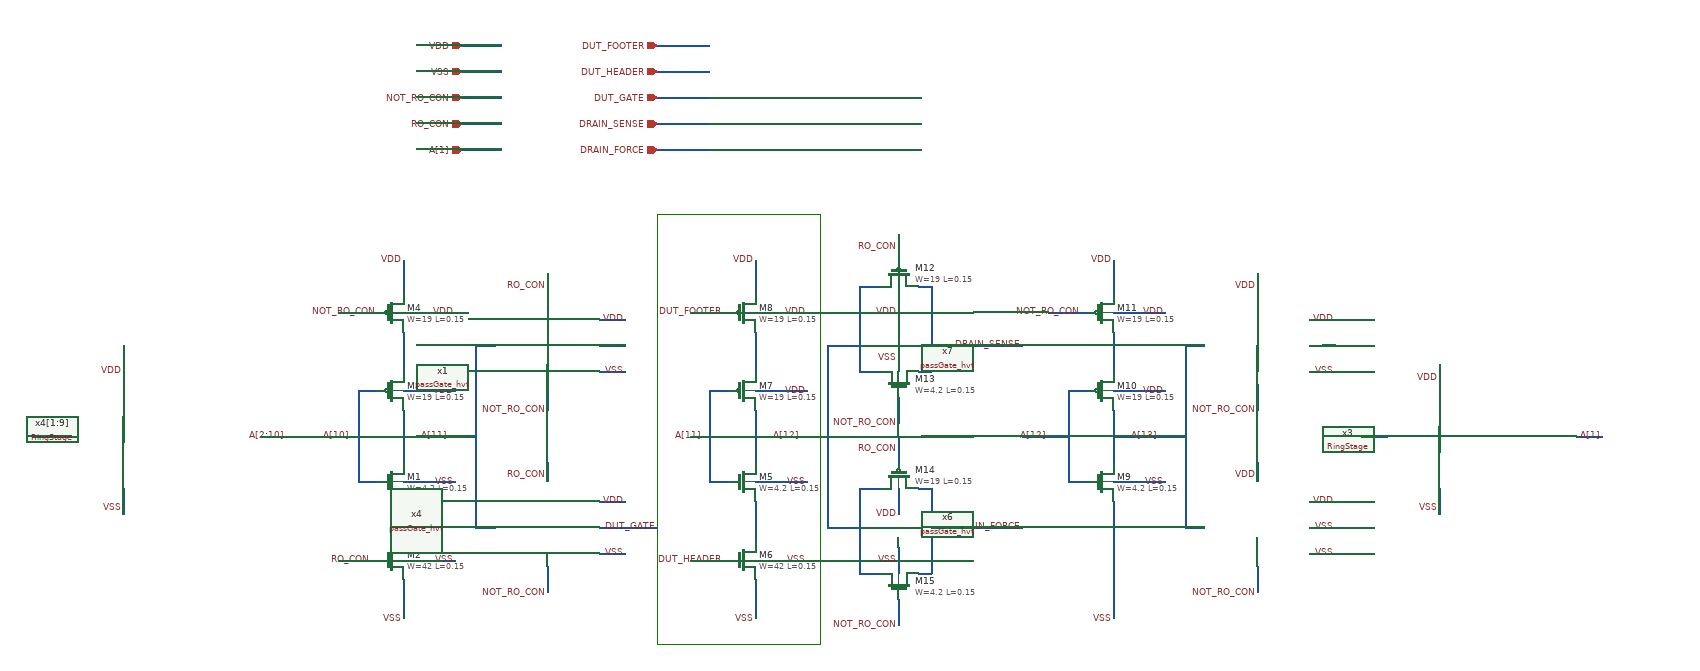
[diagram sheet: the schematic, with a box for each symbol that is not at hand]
v {xschem version=3.4.6RC file_version=1.2
}
G {}
K {}
V {}
S {}
E {}
L 4 890 -330 890 330 {}
P 4 4 890 -330 1140 -330 1140 330 890 330 {}
N 500 -150 500 -90 {
lab=#net1}
N 500 -30 500 50 {
lab=A[11]}
N 430 -60 460 -60 {
lab=A[10]}
N 430 -60 430 80 {
lab=A[10]}
N 430 80 460 80 {
lab=A[10]}
N 500 -60 580 -60 {
lab=VDD}
N 500 -180 580 -180 {
lab=VDD}
N 500 -260 500 -210 {
lab=VDD}
N 400 -180 460 -180 {
lab=NOT_RO_CON}
N 500 110 500 170 {
lab=#net2}
N 500 80 580 80 {
lab=VSS}
N 500 230 500 290 {
lab=VSS}
N 500 200 580 200 {
lab=VSS}
N 430 200 460 200 {
lab=RO_CON}
N 400 200 430 200 {
lab=RO_CON}
N 400 10 430 10 {
lab=A[10]}
N 500 10 570 10 {
lab=A[11]}
N 720 -240 720 -200 {
lab=RO_CON}
N 720 -70 720 -30 {
lab=NOT_RO_CON}
N 720 50 720 80 {
lab=RO_CON}
N 720 210 720 250 {
lab=NOT_RO_CON}
N 800 -170 840 -170 {
lab=VDD}
N 800 -90 840 -90 {
lab=VSS}
N 800 -130 840 -130 {
lab=#net3}
N 800 110 840 110 {
lab=VDD}
N 800 150 840 150 {
lab=DUT_GATE}
N 800 190 840 190 {
lab=VSS}
N 610 -130 640 -130 {
lab=A[11]}
N 610 -130 610 150 {
lab=A[11]}
N 610 150 640 150 {
lab=A[11]}
N 570 10 610 10 {
lab=A[11]}
N 1040 -150 1040 -90 {
lab=#net4}
N 1040 -30 1040 50 {
lab=A[12]}
N 970 -60 1000 -60 {
lab=A[11]}
N 970 -60 970 80 {
lab=A[11]}
N 970 80 1000 80 {
lab=A[11]}
N 1040 -60 1120 -60 {
lab=VDD}
N 1040 -180 1120 -180 {
lab=VDD}
N 1040 -260 1040 -210 {
lab=VDD}
N 940 -180 1000 -180 {
lab=DUT_FOOTER}
N 1040 110 1040 170 {
lab=#net5}
N 1040 80 1120 80 {
lab=VSS}
N 1040 230 1040 290 {
lab=VSS}
N 1040 200 1120 200 {
lab=VSS}
N 970 200 1000 200 {
lab=DUT_HEADER}
N 940 200 970 200 {
lab=DUT_HEADER}
N 940 10 970 10 {
lab=A[11]}
N 1040 10 1110 10 {
lab=A[12]}
N 1260 -300 1260 -260 {
lab=RO_CON}
N 1260 -50 1260 -10 {
lab=NOT_RO_CON}
N 1340 -130 1380 -130 {
lab=DRAIN_SENSE}
N 1340 150 1380 150 {
lab=DRAIN_FORCE}
N 1150 -130 1180 -130 {
lab=A[12]}
N 1150 -130 1150 150 {
lab=A[12]}
N 1150 150 1180 150 {
lab=A[12]}
N 1110 10 1150 10 {
lab=A[12]}
N 840 150 890 150 {
lab=DUT_GATE}
N 1380 -130 1450 -130 {
lab=DRAIN_SENSE}
N 1380 150 1450 150 {
lab=DRAIN_FORCE}
N 1590 -30 1590 50 {
lab=A[13]}
N 1590 -150 1590 -90 {
lab=#net6}
N 1590 -260 1590 -210 {
lab=VDD}
N 1590 110 1590 290 {
lab=VSS}
N 1590 80 1670 80 {
lab=VSS}
N 1590 -60 1670 -60 {
lab=VDD}
N 1590 -180 1670 -180 {
lab=VDD}
N 1520 -60 1550 -60 {
lab=A[12]}
N 1520 -60 1520 80 {
lab=A[12]}
N 1520 80 1550 80 {
lab=A[12]}
N 1470 10 1520 10 {
lab=A[12]}
N 1590 10 1660 10 {
lab=A[13]}
N 1450 10 1470 10 {
lab=A[12]}
N 1490 -180 1550 -180 {
lab=NOT_RO_CON}
N 1810 -240 1810 -200 {
lab=VDD}
N 1810 -70 1810 -30 {
lab=NOT_RO_CON}
N 1810 50 1810 80 {
lab=VDD}
N 1810 210 1810 250 {
lab=NOT_RO_CON}
N 1890 -170 1930 -170 {
lab=VDD}
N 1890 -90 1930 -90 {
lab=VSS}
N 1890 -130 1930 -130 {
lab=#net7}
N 1890 110 1930 110 {
lab=VDD}
N 1890 150 1930 150 {
lab=VSS}
N 1890 190 1930 190 {
lab=VSS}
N 1700 -130 1730 -130 {
lab=A[13]}
N 1700 -130 1700 150 {
lab=A[13]}
N 1700 150 1730 150 {
lab=A[13]}
N 1660 10 1700 10 {
lab=A[13]}
N 590 -590 650 -590 {
lab=VDD}
N 590 -550 650 -550 {
lab=VSS}
N 590 -510 650 -510 {
lab=NOT_RO_CON}
N 590 -470 650 -470 {
lab=RO_CON}
N 890 -590 970 -590 {
lab=DUT_FOOTER}
N 890 -550 970 -550 {
lab=DUT_HEADER}
N 890 -510 970 -510 {
lab=DUT_GATE}
N 890 -470 970 -470 {
lab=DRAIN_SENSE}
N 890 -430 970 -430 {
lab=DRAIN_FORCE}
N 590 -430 650 -430 {
lab=A[1]}
N 70 -130 70 -70 {
lab=VDD}
N -70 10 -10 10 {
lab=A[1:9]}
N 70 90 70 130 {
lab=VSS}
N 280 10 320 10 {
lab=A[2:10]}
N 2090 -100 2090 -70 {
lab=VDD}
N 2090 90 2090 130 {
lab=VSS}
N 2300 10 2340 10 {
lab=A[1]}
N 1970 10 2010 10 {
lab=A[101]}
N 1200 -220 1230 -220 {
lab=A[12]}
N 1200 -220 1200 -90 {
lab=A[12]}
N 1200 -90 1230 -90 {
lab=A[12]}
N 1180 -130 1200 -130 {
lab=A[12]}
N 1290 -220 1310 -220 {
lab=DRAIN_SENSE}
N 1310 -220 1310 -90 {
lab=DRAIN_SENSE}
N 1290 -90 1310 -90 {
lab=DRAIN_SENSE}
N 1310 -130 1340 -130 {
lab=DRAIN_SENSE}
N 1260 -130 1260 -90 {
lab=VSS}
N 1260 -220 1260 -180 {
lab=VDD}
N 1260 10 1260 50 {
lab=RO_CON}
N 1260 260 1260 300 {
lab=NOT_RO_CON}
N 1200 90 1230 90 {
lab=A[12]}
N 1200 90 1200 220 {
lab=A[12]}
N 1200 220 1230 220 {
lab=A[12]}
N 1290 90 1310 90 {
lab=DRAIN_FORCE}
N 1310 90 1310 220 {
lab=DRAIN_FORCE}
N 1290 220 1310 220 {
lab=DRAIN_FORCE}
N 1260 180 1260 220 {
lab=VSS}
N 1260 90 1260 130 {
lab=VDD}
N 1310 150 1340 150 {
lab=DRAIN_FORCE}
N 1180 150 1200 150 {
lab=A[12]}
C {sky130_fd_pr/pfet_01v8_hvt.sym} 480 -60 0 0 {name=M3
W=19
L=0.15
nf=1
mult=1
ad="'int((nf+1)/2) * W/nf * 0.29'" 
pd="'2*int((nf+1)/2) * (W/nf + 0.29)'"
as="'int((nf+2)/2) * W/nf * 0.29'" 
ps="'2*int((nf+2)/2) * (W/nf + 0.29)'"
nrd="'0.29 / W'" nrs="'0.29 / W'"
sa=0 sb=0 sd=0
model=pfet_01v8_hvt
spiceprefix=X
}
C {sky130_fd_pr/pfet_01v8_hvt.sym} 480 -180 0 0 {name=M4
W=19
L=0.15
nf=1
mult=10
ad="'int((nf+1)/2) * W/nf * 0.29'" 
pd="'2*int((nf+1)/2) * (W/nf + 0.29)'"
as="'int((nf+2)/2) * W/nf * 0.29'" 
ps="'2*int((nf+2)/2) * (W/nf + 0.29)'"
nrd="'0.29 / W'" nrs="'0.29 / W'"
sa=0 sb=0 sd=0
model=pfet_01v8_hvt
spiceprefix=X
}
C {lab_wire.sym} 500 -260 0 0 {name=p8 sig_type=std_logic lab=VDD}
C {lab_wire.sym} 580 -180 0 0 {name=p11 sig_type=std_logic lab=VDD}
C {lab_wire.sym} 580 -60 0 0 {name=p15 sig_type=std_logic lab=VDD}
C {lab_wire.sym} 580 80 0 0 {name=p16 sig_type=std_logic lab=VSS}
C {lab_wire.sym} 580 200 0 0 {name=p17 sig_type=std_logic lab=VSS}
C {lab_wire.sym} 500 290 0 0 {name=p18 sig_type=std_logic lab=VSS}
C {lab_wire.sym} 420 10 0 0 {name=p19 sig_type=std_logic lab=A[10]}
C {lab_wire.sym} 570 10 0 0 {name=p20 sig_type=std_logic lab=A[11]}
C {lab_wire.sym} 840 -170 0 0 {name=p23 sig_type=std_logic lab=VDD}
C {lab_wire.sym} 840 -90 0 0 {name=p24 sig_type=std_logic lab=VSS}
C {lab_wire.sym} 840 110 0 0 {name=p25 sig_type=std_logic lab=VDD}
C {lab_wire.sym} 840 190 0 0 {name=p26 sig_type=std_logic lab=VSS}
C {sky130_fd_pr/pfet_01v8_hvt.sym} 1020 -60 0 0 {name=M7
W=19
L=0.15
nf=1
mult=1
ad="'int((nf+1)/2) * W/nf * 0.29'" 
pd="'2*int((nf+1)/2) * (W/nf + 0.29)'"
as="'int((nf+2)/2) * W/nf * 0.29'" 
ps="'2*int((nf+2)/2) * (W/nf + 0.29)'"
nrd="'0.29 / W'" nrs="'0.29 / W'"
sa=0 sb=0 sd=0
model=pfet_01v8_hvt
spiceprefix=X
}
C {sky130_fd_pr/pfet_01v8_hvt.sym} 1020 -180 0 0 {name=M8
W=19
L=0.15
nf=1
mult=10
ad="'int((nf+1)/2) * W/nf * 0.29'" 
pd="'2*int((nf+1)/2) * (W/nf + 0.29)'"
as="'int((nf+2)/2) * W/nf * 0.29'" 
ps="'2*int((nf+2)/2) * (W/nf + 0.29)'"
nrd="'0.29 / W'" nrs="'0.29 / W'"
sa=0 sb=0 sd=0
model=pfet_01v8_hvt
spiceprefix=X
}
C {lab_wire.sym} 1040 -260 0 0 {name=p29 sig_type=std_logic lab=VDD}
C {lab_wire.sym} 1120 -180 0 0 {name=p30 sig_type=std_logic lab=VDD}
C {lab_wire.sym} 1120 -60 0 0 {name=p31 sig_type=std_logic lab=VDD}
C {lab_wire.sym} 1120 80 0 0 {name=p32 sig_type=std_logic lab=VSS}
C {lab_wire.sym} 1120 200 0 0 {name=p33 sig_type=std_logic lab=VSS}
C {lab_wire.sym} 1040 290 0 0 {name=p34 sig_type=std_logic lab=VSS}
C {lab_wire.sym} 960 10 0 0 {name=p35 sig_type=std_logic lab=A[11]}
C {lab_wire.sym} 1110 10 0 0 {name=p36 sig_type=std_logic lab=A[12]}
C {lab_wire.sym} 1260 -180 0 0 {name=p39 sig_type=std_logic lab=VDD}
C {lab_wire.sym} 1260 -110 0 0 {name=p40 sig_type=std_logic lab=VSS}
C {lab_wire.sym} 460 -180 0 0 {name=p45 sig_type=std_logic lab=NOT_RO_CON}
C {lab_wire.sym} 450 200 0 0 {name=p21 sig_type=std_logic lab=RO_CON}
C {lab_wire.sym} 720 70 0 0 {name=p22 sig_type=std_logic lab=RO_CON}
C {lab_wire.sym} 720 -220 0 0 {name=p27 sig_type=std_logic lab=RO_CON}
C {lab_wire.sym} 720 -30 0 0 {name=p28 sig_type=std_logic lab=NOT_RO_CON}
C {lab_wire.sym} 720 250 0 0 {name=p37 sig_type=std_logic lab=NOT_RO_CON}
C {lab_wire.sym} 890 150 0 0 {name=p38 sig_type=std_logic lab=DUT_GATE}
C {lab_wire.sym} 990 -180 0 0 {name=p43 sig_type=std_logic lab=DUT_FOOTER}
C {lab_wire.sym} 990 200 0 0 {name=p44 sig_type=std_logic lab=DUT_HEADER}
C {lab_wire.sym} 1260 -280 0 0 {name=p46 sig_type=std_logic lab=RO_CON}
C {lab_wire.sym} 1260 -10 0 0 {name=p47 sig_type=std_logic lab=NOT_RO_CON}
C {lab_wire.sym} 1450 -130 0 0 {name=p50 sig_type=std_logic lab=DRAIN_SENSE}
C {lab_wire.sym} 1450 150 0 0 {name=p51 sig_type=std_logic lab=DRAIN_FORCE}
C {sky130_fd_pr/pfet_01v8_hvt.sym} 1570 -60 0 0 {name=M10
W=19
L=0.15
nf=1
mult=1
ad="'int((nf+1)/2) * W/nf * 0.29'" 
pd="'2*int((nf+1)/2) * (W/nf + 0.29)'"
as="'int((nf+2)/2) * W/nf * 0.29'" 
ps="'2*int((nf+2)/2) * (W/nf + 0.29)'"
nrd="'0.29 / W'" nrs="'0.29 / W'"
sa=0 sb=0 sd=0
model=pfet_01v8_hvt
spiceprefix=X
}
C {sky130_fd_pr/pfet_01v8_hvt.sym} 1570 -180 0 0 {name=M11
W=19
L=0.15
nf=1
mult=10
ad="'int((nf+1)/2) * W/nf * 0.29'" 
pd="'2*int((nf+1)/2) * (W/nf + 0.29)'"
as="'int((nf+2)/2) * W/nf * 0.29'" 
ps="'2*int((nf+2)/2) * (W/nf + 0.29)'"
nrd="'0.29 / W'" nrs="'0.29 / W'"
sa=0 sb=0 sd=0
model=pfet_01v8_hvt
spiceprefix=X
}
C {lab_wire.sym} 1590 290 0 0 {name=p52 sig_type=std_logic lab=VSS}
C {lab_wire.sym} 1590 -260 0 0 {name=p53 sig_type=std_logic lab=VDD}
C {lab_wire.sym} 1670 -180 0 0 {name=p54 sig_type=std_logic lab=VDD}
C {lab_wire.sym} 1670 -60 0 0 {name=p55 sig_type=std_logic lab=VDD}
C {lab_wire.sym} 1670 80 0 0 {name=p56 sig_type=std_logic lab=VSS}
C {lab_wire.sym} 1490 10 0 0 {name=p57 sig_type=std_logic lab=A[12]}
C {lab_wire.sym} 1660 10 0 0 {name=p58 sig_type=std_logic lab=A[13]}
C {lab_wire.sym} 1540 -180 0 0 {name=p59 sig_type=std_logic lab=NOT_RO_CON}
C {lab_wire.sym} 1930 -170 0 0 {name=p60 sig_type=std_logic lab=VDD}
C {lab_wire.sym} 1930 -90 0 0 {name=p61 sig_type=std_logic lab=VSS}
C {lab_wire.sym} 1930 110 0 0 {name=p62 sig_type=std_logic lab=VDD}
C {lab_wire.sym} 1930 190 0 0 {name=p63 sig_type=std_logic lab=VSS}
C {lab_wire.sym} 1810 -220 0 0 {name=p64 sig_type=std_logic lab=VDD}
C {lab_wire.sym} 1810 -30 0 0 {name=p65 sig_type=std_logic lab=NOT_RO_CON}
C {lab_wire.sym} 1810 70 0 0 {name=p66 sig_type=std_logic lab=VDD}
C {lab_wire.sym} 1810 250 0 0 {name=p67 sig_type=std_logic lab=NOT_RO_CON}
C {lab_wire.sym} 1930 150 0 0 {name=p68 sig_type=std_logic lab=VSS}
C {iopin.sym} 590 -590 2 0 {name=p81 lab=VDD}
C {iopin.sym} 590 -550 2 0 {name=p82 lab=VSS}
C {iopin.sym} 590 -510 2 0 {name=p83 lab=NOT_RO_CON}
C {iopin.sym} 590 -470 2 0 {name=p84 lab=RO_CON}
C {iopin.sym} 890 -590 2 0 {name=p85 lab=DUT_FOOTER}
C {iopin.sym} 890 -550 2 0 {name=p86 lab=DUT_HEADER}
C {iopin.sym} 890 -510 2 0 {name=p87 lab=DUT_GATE}
C {iopin.sym} 890 -470 2 0 {name=p88 lab=DRAIN_SENSE}
C {iopin.sym} 890 -430 2 0 {name=p89 lab=DRAIN_FORCE}
C {iopin.sym} 590 -430 2 0 {name=p90 lab=A[1]}
C {sky130_fd_pr/nfet_01v8.sym} 480 80 0 0 {name=M1
W=4.2
L=0.15
nf=1 
mult=1
ad="'int((nf+1)/2) * W/nf * 0.29'" 
pd="'2*int((nf+1)/2) * (W/nf + 0.29)'"
as="'int((nf+2)/2) * W/nf * 0.29'" 
ps="'2*int((nf+2)/2) * (W/nf + 0.29)'"
nrd="'0.29 / W'" nrs="'0.29 / W'"
sa=0 sb=0 sd=0
model=nfet_01v8
spiceprefix=X
}
C {sky130_fd_pr/nfet_01v8.sym} 480 200 0 0 {name=M2
W=42
L=0.15
nf=1 
mult=1
ad="'int((nf+1)/2) * W/nf * 0.29'" 
pd="'2*int((nf+1)/2) * (W/nf + 0.29)'"
as="'int((nf+2)/2) * W/nf * 0.29'" 
ps="'2*int((nf+2)/2) * (W/nf + 0.29)'"
nrd="'0.29 / W'" nrs="'0.29 / W'"
sa=0 sb=0 sd=0
model=nfet_01v8
spiceprefix=X
}
C {sky130_fd_pr/nfet_01v8.sym} 1020 80 0 0 {name=M5
W=4.2
L=0.15
nf=1 
mult=1
ad="'int((nf+1)/2) * W/nf * 0.29'" 
pd="'2*int((nf+1)/2) * (W/nf + 0.29)'"
as="'int((nf+2)/2) * W/nf * 0.29'" 
ps="'2*int((nf+2)/2) * (W/nf + 0.29)'"
nrd="'0.29 / W'" nrs="'0.29 / W'"
sa=0 sb=0 sd=0
model=nfet_01v8
spiceprefix=X
}
C {sky130_fd_pr/nfet_01v8.sym} 1020 200 0 0 {name=M6
W=42
L=0.15
nf=1 
mult=1
ad="'int((nf+1)/2) * W/nf * 0.29'" 
pd="'2*int((nf+1)/2) * (W/nf + 0.29)'"
as="'int((nf+2)/2) * W/nf * 0.29'" 
ps="'2*int((nf+2)/2) * (W/nf + 0.29)'"
nrd="'0.29 / W'" nrs="'0.29 / W'"
sa=0 sb=0 sd=0
model=nfet_01v8
spiceprefix=X
}
C {sky130_fd_pr/nfet_01v8.sym} 1570 80 0 0 {name=M9
W=4.2
L=0.15
nf=1 
mult=1
ad="'int((nf+1)/2) * W/nf * 0.29'" 
pd="'2*int((nf+1)/2) * (W/nf + 0.29)'"
as="'int((nf+2)/2) * W/nf * 0.29'" 
ps="'2*int((nf+2)/2) * (W/nf + 0.29)'"
nrd="'0.29 / W'" nrs="'0.29 / W'"
sa=0 sb=0 sd=0
model=nfet_01v8
spiceprefix=X
}
C {lab_wire.sym} 70 -90 0 0 {name=p1 sig_type=std_logic lab=VDD}
C {lab_wire.sym} 70 120 0 0 {name=p2 sig_type=std_logic lab=VSS}
C {lab_wire.sym} -30 10 0 0 {name=p3 sig_type=std_logic lab=A[1:9]}
C {lab_wire.sym} 320 10 0 0 {name=p4 sig_type=std_logic lab=A[2:10]}
C {lab_wire.sym} 2090 -80 0 0 {name=p5 sig_type=std_logic lab=VDD}
C {lab_wire.sym} 2090 120 0 0 {name=p6 sig_type=std_logic lab=VSS}
C {lab_wire.sym} 1990 10 0 0 {name=p7 sig_type=std_logic lab=A[13]}
C {lab_wire.sym} 2340 10 0 0 {name=p9 sig_type=std_logic lab=A[1]}
C {/foss/designs/RO_Aging_UNICASS/HVT/RingStage/RingStage.sym} 160 10 0 0 {name=x4[1:9]}
C {/foss/designs/RO_Aging_UNICASS/HVT/passGate_hvt/passGate_hvt.sym} 380 -40 0 0 {name=x1}
C {/foss/designs/RO_Aging_UNICASS/HVT/passGate_hvt/passGate_hvt.sym} 380 240 0 0 {name=x4}
C {/foss/designs/RO_Aging_UNICASS/HVT/passGate_hvt/passGate_hvt.sym} 1470 240 0 0 {name=x6}
C {/foss/designs/RO_Aging_UNICASS/HVT/passGate_hvt/passGate_hvt.sym} 1470 -40 0 0 {name=x7}
C {/foss/designs/RO_Aging_UNICASS/HVT/RingStage/RingStage.sym} 2180 10 0 0 {name=x3}
C {sky130_fd_pr/pfet_01v8_hvt.sym} 1260 -240 1 0 {name=M12
W=19
L=0.15
nf=1
mult=1
ad="'int((nf+1)/2) * W/nf * 0.29'" 
pd="'2*int((nf+1)/2) * (W/nf + 0.29)'"
as="'int((nf+2)/2) * W/nf * 0.29'" 
ps="'2*int((nf+2)/2) * (W/nf + 0.29)'"
nrd="'0.29 / W'" nrs="'0.29 / W'"
sa=0 sb=0 sd=0
model=pfet_01v8_hvt
spiceprefix=X
}
C {sky130_fd_pr/nfet_01v8.sym} 1260 -70 3 0 {name=M13
W=4.2
L=0.15
nf=1 
mult=1
ad="'int((nf+1)/2) * W/nf * 0.29'" 
pd="'2*int((nf+1)/2) * (W/nf + 0.29)'"
as="'int((nf+2)/2) * W/nf * 0.29'" 
ps="'2*int((nf+2)/2) * (W/nf + 0.29)'"
nrd="'0.29 / W'" nrs="'0.29 / W'"
sa=0 sb=0 sd=0
model=nfet_01v8
spiceprefix=X
}
C {lab_wire.sym} 1260 130 0 0 {name=p10 sig_type=std_logic lab=VDD}
C {lab_wire.sym} 1260 200 0 0 {name=p12 sig_type=std_logic lab=VSS}
C {lab_wire.sym} 1260 30 0 0 {name=p13 sig_type=std_logic lab=RO_CON}
C {lab_wire.sym} 1260 300 0 0 {name=p14 sig_type=std_logic lab=NOT_RO_CON}
C {sky130_fd_pr/pfet_01v8_hvt.sym} 1260 70 1 0 {name=M14
W=19
L=0.15
nf=1
mult=1
ad="'int((nf+1)/2) * W/nf * 0.29'" 
pd="'2*int((nf+1)/2) * (W/nf + 0.29)'"
as="'int((nf+2)/2) * W/nf * 0.29'" 
ps="'2*int((nf+2)/2) * (W/nf + 0.29)'"
nrd="'0.29 / W'" nrs="'0.29 / W'"
sa=0 sb=0 sd=0
model=pfet_01v8_hvt
spiceprefix=X
}
C {sky130_fd_pr/nfet_01v8.sym} 1260 240 3 0 {name=M15
W=4.2
L=0.15
nf=1 
mult=1
ad="'int((nf+1)/2) * W/nf * 0.29'" 
pd="'2*int((nf+1)/2) * (W/nf + 0.29)'"
as="'int((nf+2)/2) * W/nf * 0.29'" 
ps="'2*int((nf+2)/2) * (W/nf + 0.29)'"
nrd="'0.29 / W'" nrs="'0.29 / W'"
sa=0 sb=0 sd=0
model=nfet_01v8
spiceprefix=X
}
